# aion_layout: rewrote 'CLASS BLOCK ;' to 'CLASS CORE ;': magic reads no cell class out of a GDS and defaults to BLOCK, which OpenROAD treats as a hard macro
# aion_layout: inserted 'SITE CoreSite ;' after SIZE: magic emits no SITE, and without one the placer has no row to legalise the cell into
# aion_layout: inserted 'SYMMETRY X Y ;' after SIZE: magic emits no SYMMETRY, and without it the detailed placer will not put the cell in a flipped row
# aion_layout: inserted 'DIRECTION INPUT ;' on PIN I1: magic writes no pin direction, and a LEF pin without one is read as an input
# aion_layout: inserted 'DIRECTION INPUT ;' on PIN I0: magic writes no pin direction, and a LEF pin without one is read as an input
# aion_layout: inserted 'DIRECTION INPUT ;' on PIN I3: magic writes no pin direction, and a LEF pin without one is read as an input
# aion_layout: inserted 'DIRECTION INPUT ;' on PIN I2: magic writes no pin direction, and a LEF pin without one is read as an input
# aion_layout: inserted 'DIRECTION INOUT ;' on PIN VDD: magic writes no pin direction, and a LEF pin without one is read as an input
# aion_layout: inserted 'DIRECTION INOUT ;' on PIN VSS: magic writes no pin direction, and a LEF pin without one is read as an input
# aion_layout: inserted 'DIRECTION OUTPUT ;' on PIN O0: magic writes no pin direction, and a LEF pin without one is read as an input
VERSION 5.7 ;
  NOWIREEXTENSIONATPIN ON ;
  DIVIDERCHAR "/" ;
  BUSBITCHARS "[]" ;
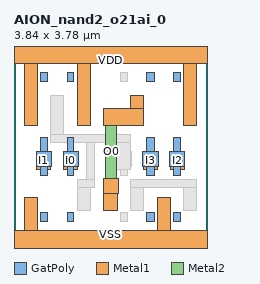
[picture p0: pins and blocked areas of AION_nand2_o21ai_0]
MACRO AION_nand2_o21ai_0
  CLASS CORE ;
  FOREIGN AION_nand2_o21ai_0 ;
  ORIGIN 0.000 0.000 ;
  SIZE 3.840 BY 3.780 ;
  SYMMETRY X Y ;
  SITE CoreSite ;
  PIN I1
    DIRECTION INPUT ;
    ANTENNAGATEAREA 0.241800 ;
    PORT
      LAYER GatPoly ;
        RECT 0.530 3.195 0.660 3.375 ;
        RECT 0.530 1.800 0.660 2.075 ;
        RECT 0.445 1.500 0.745 1.800 ;
        RECT 0.530 1.330 0.660 1.500 ;
        RECT 0.530 0.410 0.660 0.590 ;
      LAYER Metal1 ;
        RECT 0.455 1.450 0.735 1.790 ;
    END
  END I1
  PIN I0
    DIRECTION INPUT ;
    ANTENNAGATEAREA 0.241800 ;
    PORT
      LAYER GatPoly ;
        RECT 1.060 3.195 1.190 3.375 ;
        RECT 1.060 1.800 1.190 2.075 ;
        RECT 0.975 1.500 1.275 1.800 ;
        RECT 1.060 1.330 1.190 1.500 ;
        RECT 1.060 0.410 1.190 0.590 ;
      LAYER Metal1 ;
        RECT 0.985 1.450 1.265 1.790 ;
    END
  END I0
  PIN I3
    DIRECTION INPUT ;
    ANTENNAGATEAREA 0.279000 ;
    PORT
      LAYER GatPoly ;
        RECT 2.640 3.195 2.790 3.375 ;
        RECT 2.640 1.800 2.790 2.075 ;
        RECT 2.565 1.500 2.865 1.800 ;
        RECT 2.640 1.330 2.790 1.500 ;
        RECT 2.640 0.410 2.790 0.590 ;
      LAYER Metal1 ;
        RECT 2.575 1.450 2.855 1.790 ;
    END
  END I3
  PIN I2
    DIRECTION INPUT ;
    ANTENNAGATEAREA 0.279000 ;
    PORT
      LAYER GatPoly ;
        RECT 3.170 3.195 3.320 3.375 ;
        RECT 3.170 1.800 3.320 2.075 ;
        RECT 3.095 1.500 3.395 1.800 ;
        RECT 3.170 1.330 3.320 1.500 ;
        RECT 3.170 0.410 3.320 0.590 ;
      LAYER Metal1 ;
        RECT 3.105 1.450 3.385 1.790 ;
    END
  END I2
  PIN VDD
    DIRECTION INOUT ;
    USE POWER ;
    PORT
      LAYER Metal1 ;
        RECT 0.000 3.560 3.840 4.000 ;
        RECT 0.200 2.310 0.460 3.560 ;
        RECT 1.260 2.310 1.520 3.560 ;
        RECT 3.380 2.310 3.640 3.560 ;
    END
  END VDD
  PIN VSS
    DIRECTION INOUT ;
    USE GROUND ;
    PORT
      LAYER Metal1 ;
        RECT 0.200 0.220 0.460 0.880 ;
        RECT 2.850 0.220 3.110 0.880 ;
        RECT 0.000 -0.220 3.840 0.220 ;
    END
  END VSS
  PIN O0
    DIRECTION OUTPUT ;
    ANTENNADIFFAREA 0.677200 ;
    PORT
      LAYER Metal1 ;
        RECT 2.320 2.660 2.580 2.910 ;
        RECT 1.790 2.310 2.580 2.660 ;
        RECT 1.790 0.960 2.080 1.270 ;
        RECT 1.790 0.620 2.050 0.960 ;
      LAYER Metal2 ;
        RECT 1.825 0.950 2.045 2.650 ;
    END
  END O0
  OBS
      LAYER GatPoly ;
        RECT 2.110 3.195 2.260 3.375 ;
        RECT 2.110 1.800 2.260 2.075 ;
        RECT 2.035 1.500 2.335 1.800 ;
        RECT 2.110 1.330 2.260 1.500 ;
        RECT 2.110 0.410 2.260 0.590 ;
      LAYER Metal1 ;
        RECT 0.730 2.130 0.990 2.910 ;
        RECT 0.730 1.970 2.325 2.130 ;
        RECT 1.445 1.250 1.605 1.970 ;
        RECT 2.045 1.450 2.325 1.970 ;
        RECT 1.260 1.090 1.605 1.250 ;
        RECT 2.320 1.090 3.640 1.250 ;
        RECT 1.260 0.620 1.520 1.090 ;
        RECT 2.320 0.620 2.580 1.090 ;
        RECT 3.380 0.620 3.640 1.090 ;
  END
END AION_nand2_o21ai_0
END LIBRARY

